VERSION 5.4 ;
NAMESCASESENSITIVE ON ;
BUSBITCHARS "[]" ;
DIVIDERCHAR "/" ;
UNITS
  DATABASE MICRONS 2000 ;
END UNITS
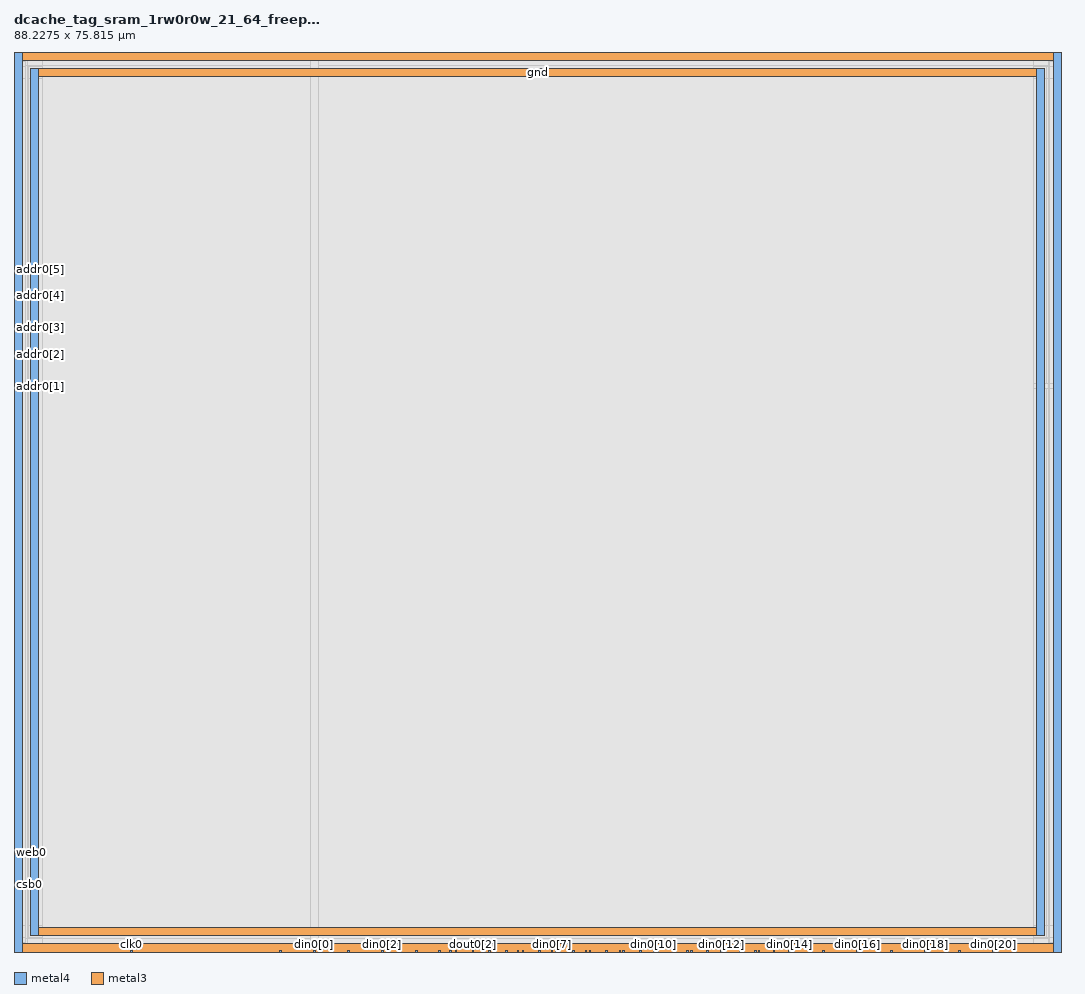
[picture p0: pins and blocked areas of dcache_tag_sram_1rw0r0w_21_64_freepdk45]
MACRO dcache_tag_sram_1rw0r0w_21_64_freepdk45
   CLASS BLOCK ;
   SIZE 88.2275 BY 75.815 ;
   SYMMETRY X Y R90 ;
   PIN din0[0]
      DIRECTION INPUT ;
      PORT
         LAYER metal4 ;
         RECT  25.2325 0.0 25.3725 0.14 ;
      END
   END din0[0]
   PIN din0[1]
      DIRECTION INPUT ;
      PORT
         LAYER metal4 ;
         RECT  28.0925 0.0 28.2325 0.14 ;
      END
   END din0[1]
   PIN din0[2]
      DIRECTION INPUT ;
      PORT
         LAYER metal4 ;
         RECT  30.9525 0.0 31.0925 0.14 ;
      END
   END din0[2]
   PIN din0[3]
      DIRECTION INPUT ;
      PORT
         LAYER metal4 ;
         RECT  33.8125 0.0 33.9525 0.14 ;
      END
   END din0[3]
   PIN din0[4]
      DIRECTION INPUT ;
      PORT
         LAYER metal4 ;
         RECT  36.6725 0.0 36.8125 0.14 ;
      END
   END din0[4]
   PIN din0[5]
      DIRECTION INPUT ;
      PORT
         LAYER metal4 ;
         RECT  39.5325 0.0 39.6725 0.14 ;
      END
   END din0[5]
   PIN din0[6]
      DIRECTION INPUT ;
      PORT
         LAYER metal4 ;
         RECT  42.3925 0.0 42.5325 0.14 ;
      END
   END din0[6]
   PIN din0[7]
      DIRECTION INPUT ;
      PORT
         LAYER metal4 ;
         RECT  45.2525 0.0 45.3925 0.14 ;
      END
   END din0[7]
   PIN din0[8]
      DIRECTION INPUT ;
      PORT
         LAYER metal4 ;
         RECT  48.1125 0.0 48.2525 0.14 ;
      END
   END din0[8]
   PIN din0[9]
      DIRECTION INPUT ;
      PORT
         LAYER metal4 ;
         RECT  50.9725 0.0 51.1125 0.14 ;
      END
   END din0[9]
   PIN din0[10]
      DIRECTION INPUT ;
      PORT
         LAYER metal4 ;
         RECT  53.8325 0.0 53.9725 0.14 ;
      END
   END din0[10]
   PIN din0[11]
      DIRECTION INPUT ;
      PORT
         LAYER metal4 ;
         RECT  56.6925 0.0 56.8325 0.14 ;
      END
   END din0[11]
   PIN din0[12]
      DIRECTION INPUT ;
      PORT
         LAYER metal4 ;
         RECT  59.5525 0.0 59.6925 0.14 ;
      END
   END din0[12]
   PIN din0[13]
      DIRECTION INPUT ;
      PORT
         LAYER metal4 ;
         RECT  62.4125 0.0 62.5525 0.14 ;
      END
   END din0[13]
   PIN din0[14]
      DIRECTION INPUT ;
      PORT
         LAYER metal4 ;
         RECT  65.2725 0.0 65.4125 0.14 ;
      END
   END din0[14]
   PIN din0[15]
      DIRECTION INPUT ;
      PORT
         LAYER metal4 ;
         RECT  68.1325 0.0 68.2725 0.14 ;
      END
   END din0[15]
   PIN din0[16]
      DIRECTION INPUT ;
      PORT
         LAYER metal4 ;
         RECT  70.9925 0.0 71.1325 0.14 ;
      END
   END din0[16]
   PIN din0[17]
      DIRECTION INPUT ;
      PORT
         LAYER metal4 ;
         RECT  73.8525 0.0 73.9925 0.14 ;
      END
   END din0[17]
   PIN din0[18]
      DIRECTION INPUT ;
      PORT
         LAYER metal4 ;
         RECT  76.7125 0.0 76.8525 0.14 ;
      END
   END din0[18]
   PIN din0[19]
      DIRECTION INPUT ;
      PORT
         LAYER metal4 ;
         RECT  79.5725 0.0 79.7125 0.14 ;
      END
   END din0[19]
   PIN din0[20]
      DIRECTION INPUT ;
      PORT
         LAYER metal4 ;
         RECT  82.4325 0.0 82.5725 0.14 ;
      END
   END din0[20]
   PIN addr0[0]
      DIRECTION INPUT ;
      PORT
         LAYER metal4 ;
         RECT  22.3725 0.0 22.5125 0.14 ;
      END
   END addr0[0]
   PIN addr0[1]
      DIRECTION INPUT ;
      PORT
         LAYER metal3 ;
         RECT  0.0 47.57 0.14 47.71 ;
      END
   END addr0[1]
   PIN addr0[2]
      DIRECTION INPUT ;
      PORT
         LAYER metal3 ;
         RECT  0.0 50.3 0.14 50.44 ;
      END
   END addr0[2]
   PIN addr0[3]
      DIRECTION INPUT ;
      PORT
         LAYER metal3 ;
         RECT  0.0 52.51 0.14 52.65 ;
      END
   END addr0[3]
   PIN addr0[4]
      DIRECTION INPUT ;
      PORT
         LAYER metal3 ;
         RECT  0.0 55.24 0.14 55.38 ;
      END
   END addr0[4]
   PIN addr0[5]
      DIRECTION INPUT ;
      PORT
         LAYER metal3 ;
         RECT  0.0 57.45 0.14 57.59 ;
      END
   END addr0[5]
   PIN csb0
      DIRECTION INPUT ;
      PORT
         LAYER metal3 ;
         RECT  0.0 5.58 0.14 5.72 ;
      END
   END csb0
   PIN web0
      DIRECTION INPUT ;
      PORT
         LAYER metal3 ;
         RECT  0.0 8.31 0.14 8.45 ;
      END
   END web0
   PIN clk0
      DIRECTION INPUT ;
      PORT
         LAYER metal4 ;
         RECT  9.84 0.0 9.98 0.14 ;
      END
   END clk0
   PIN dout0[0]
      DIRECTION OUTPUT ;
      PORT
         LAYER metal4 ;
         RECT  35.7625 0.0 35.9025 0.14 ;
      END
   END dout0[0]
   PIN dout0[1]
      DIRECTION OUTPUT ;
      PORT
         LAYER metal4 ;
         RECT  37.1725 0.0 37.3125 0.14 ;
      END
   END dout0[1]
   PIN dout0[2]
      DIRECTION OUTPUT ;
      PORT
         LAYER metal4 ;
         RECT  38.5825 0.0 38.7225 0.14 ;
      END
   END dout0[2]
   PIN dout0[3]
      DIRECTION OUTPUT ;
      PORT
         LAYER metal4 ;
         RECT  39.9925 0.0 40.1325 0.14 ;
      END
   END dout0[3]
   PIN dout0[4]
      DIRECTION OUTPUT ;
      PORT
         LAYER metal4 ;
         RECT  41.4025 0.0 41.5425 0.14 ;
      END
   END dout0[4]
   PIN dout0[5]
      DIRECTION OUTPUT ;
      PORT
         LAYER metal4 ;
         RECT  42.8125 0.0 42.9525 0.14 ;
      END
   END dout0[5]
   PIN dout0[6]
      DIRECTION OUTPUT ;
      PORT
         LAYER metal4 ;
         RECT  44.2225 0.0 44.3625 0.14 ;
      END
   END dout0[6]
   PIN dout0[7]
      DIRECTION OUTPUT ;
      PORT
         LAYER metal4 ;
         RECT  45.6325 0.0 45.7725 0.14 ;
      END
   END dout0[7]
   PIN dout0[8]
      DIRECTION OUTPUT ;
      PORT
         LAYER metal4 ;
         RECT  47.0425 0.0 47.1825 0.14 ;
      END
   END dout0[8]
   PIN dout0[9]
      DIRECTION OUTPUT ;
      PORT
         LAYER metal4 ;
         RECT  48.4525 0.0 48.5925 0.14 ;
      END
   END dout0[9]
   PIN dout0[10]
      DIRECTION OUTPUT ;
      PORT
         LAYER metal4 ;
         RECT  49.8625 0.0 50.0025 0.14 ;
      END
   END dout0[10]
   PIN dout0[11]
      DIRECTION OUTPUT ;
      PORT
         LAYER metal4 ;
         RECT  51.2725 0.0 51.4125 0.14 ;
      END
   END dout0[11]
   PIN dout0[12]
      DIRECTION OUTPUT ;
      PORT
         LAYER metal4 ;
         RECT  52.6825 0.0 52.8225 0.14 ;
      END
   END dout0[12]
   PIN dout0[13]
      DIRECTION OUTPUT ;
      PORT
         LAYER metal4 ;
         RECT  54.1175 0.0 54.2575 0.14 ;
      END
   END dout0[13]
   PIN dout0[14]
      DIRECTION OUTPUT ;
      PORT
         LAYER metal4 ;
         RECT  55.5025 0.0 55.6425 0.14 ;
      END
   END dout0[14]
   PIN dout0[15]
      DIRECTION OUTPUT ;
      PORT
         LAYER metal4 ;
         RECT  56.985 0.0 57.125 0.14 ;
      END
   END dout0[15]
   PIN dout0[16]
      DIRECTION OUTPUT ;
      PORT
         LAYER metal4 ;
         RECT  58.3225 0.0 58.4625 0.14 ;
      END
   END dout0[16]
   PIN dout0[17]
      DIRECTION OUTPUT ;
      PORT
         LAYER metal4 ;
         RECT  59.8375 0.0 59.9775 0.14 ;
      END
   END dout0[17]
   PIN dout0[18]
      DIRECTION OUTPUT ;
      PORT
         LAYER metal4 ;
         RECT  61.1425 0.0 61.2825 0.14 ;
      END
   END dout0[18]
   PIN dout0[19]
      DIRECTION OUTPUT ;
      PORT
         LAYER metal4 ;
         RECT  62.6975 0.0 62.8375 0.14 ;
      END
   END dout0[19]
   PIN dout0[20]
      DIRECTION OUTPUT ;
      PORT
         LAYER metal4 ;
         RECT  63.9625 0.0 64.1025 0.14 ;
      END
   END dout0[20]
   PIN vdd
      DIRECTION INOUT ;
      USE POWER ; 
      SHAPE ABUTMENT ; 
      PORT
         LAYER metal4 ;
         RECT  87.5275 0.0 88.2275 75.815 ;
         LAYER metal3 ;
         RECT  0.0 0.0 88.2275 0.7 ;
         LAYER metal4 ;
         RECT  0.0 0.0 0.7 75.815 ;
         LAYER metal3 ;
         RECT  0.0 75.115 88.2275 75.815 ;
      END
   END vdd
   PIN gnd
      DIRECTION INOUT ;
      USE GROUND ; 
      SHAPE ABUTMENT ; 
      PORT
         LAYER metal3 ;
         RECT  1.4 1.4 86.8275 2.1 ;
         LAYER metal4 ;
         RECT  1.4 1.4 2.1 74.415 ;
         LAYER metal4 ;
         RECT  86.1275 1.4 86.8275 74.415 ;
         LAYER metal3 ;
         RECT  1.4 73.715 86.8275 74.415 ;
      END
   END gnd
   OBS
   LAYER  metal1 ;
      RECT  0.14 0.14 88.0875 75.675 ;
   LAYER  metal2 ;
      RECT  0.14 0.14 88.0875 75.675 ;
   LAYER  metal3 ;
      RECT  0.28 47.43 88.0875 47.85 ;
      RECT  0.14 47.85 0.28 50.16 ;
      RECT  0.14 50.58 0.28 52.37 ;
      RECT  0.14 52.79 0.28 55.1 ;
      RECT  0.14 55.52 0.28 57.31 ;
      RECT  0.14 5.86 0.28 8.17 ;
      RECT  0.14 8.59 0.28 47.43 ;
      RECT  0.14 0.84 0.28 5.44 ;
      RECT  0.14 57.73 0.28 74.975 ;
      RECT  0.28 0.84 1.26 1.26 ;
      RECT  0.28 1.26 1.26 2.24 ;
      RECT  0.28 2.24 1.26 47.43 ;
      RECT  1.26 0.84 86.9675 1.26 ;
      RECT  1.26 2.24 86.9675 47.43 ;
      RECT  86.9675 0.84 88.0875 1.26 ;
      RECT  86.9675 1.26 88.0875 2.24 ;
      RECT  86.9675 2.24 88.0875 47.43 ;
      RECT  0.28 47.85 1.26 73.575 ;
      RECT  0.28 73.575 1.26 74.555 ;
      RECT  0.28 74.555 1.26 74.975 ;
      RECT  1.26 47.85 86.9675 73.575 ;
      RECT  1.26 74.555 86.9675 74.975 ;
      RECT  86.9675 47.85 88.0875 73.575 ;
      RECT  86.9675 73.575 88.0875 74.555 ;
      RECT  86.9675 74.555 88.0875 74.975 ;
   LAYER  metal4 ;
      RECT  24.9525 0.42 25.6525 75.675 ;
      RECT  25.6525 0.14 27.8125 0.42 ;
      RECT  28.5125 0.14 30.6725 0.42 ;
      RECT  31.3725 0.14 33.5325 0.42 ;
      RECT  65.6925 0.14 67.8525 0.42 ;
      RECT  68.5525 0.14 70.7125 0.42 ;
      RECT  71.4125 0.14 73.5725 0.42 ;
      RECT  74.2725 0.14 76.4325 0.42 ;
      RECT  77.1325 0.14 79.2925 0.42 ;
      RECT  79.9925 0.14 82.1525 0.42 ;
      RECT  22.7925 0.14 24.9525 0.42 ;
      RECT  10.26 0.14 22.0925 0.42 ;
      RECT  34.2325 0.14 35.4825 0.42 ;
      RECT  36.1825 0.14 36.3925 0.42 ;
      RECT  37.5925 0.14 38.3025 0.42 ;
      RECT  39.0025 0.14 39.2525 0.42 ;
      RECT  40.4125 0.14 41.1225 0.42 ;
      RECT  41.8225 0.14 42.1125 0.42 ;
      RECT  43.2325 0.14 43.9425 0.42 ;
      RECT  44.6425 0.14 44.9725 0.42 ;
      RECT  46.0525 0.14 46.7625 0.42 ;
      RECT  47.4625 0.14 47.8325 0.42 ;
      RECT  48.8725 0.14 49.5825 0.42 ;
      RECT  50.2825 0.14 50.6925 0.42 ;
      RECT  51.6925 0.14 52.4025 0.42 ;
      RECT  53.1025 0.14 53.5525 0.42 ;
      RECT  54.5375 0.14 55.2225 0.42 ;
      RECT  55.9225 0.14 56.4125 0.42 ;
      RECT  57.405 0.14 58.0425 0.42 ;
      RECT  58.7425 0.14 59.2725 0.42 ;
      RECT  60.2575 0.14 60.8625 0.42 ;
      RECT  61.5625 0.14 62.1325 0.42 ;
      RECT  63.1175 0.14 63.6825 0.42 ;
      RECT  64.3825 0.14 64.9925 0.42 ;
      RECT  82.8525 0.14 87.2475 0.42 ;
      RECT  0.98 0.14 9.56 0.42 ;
      RECT  0.98 0.42 1.12 1.12 ;
      RECT  0.98 1.12 1.12 74.695 ;
      RECT  0.98 74.695 1.12 75.675 ;
      RECT  1.12 0.42 2.38 1.12 ;
      RECT  1.12 74.695 2.38 75.675 ;
      RECT  2.38 0.42 24.9525 1.12 ;
      RECT  2.38 1.12 24.9525 74.695 ;
      RECT  2.38 74.695 24.9525 75.675 ;
      RECT  25.6525 0.42 85.8475 1.12 ;
      RECT  25.6525 1.12 85.8475 74.695 ;
      RECT  25.6525 74.695 85.8475 75.675 ;
      RECT  85.8475 0.42 87.1075 1.12 ;
      RECT  85.8475 74.695 87.1075 75.675 ;
      RECT  87.1075 0.42 87.2475 1.12 ;
      RECT  87.1075 1.12 87.2475 74.695 ;
      RECT  87.1075 74.695 87.2475 75.675 ;
   END
END    dcache_tag_sram_1rw0r0w_21_64_freepdk45
END    LIBRARY
